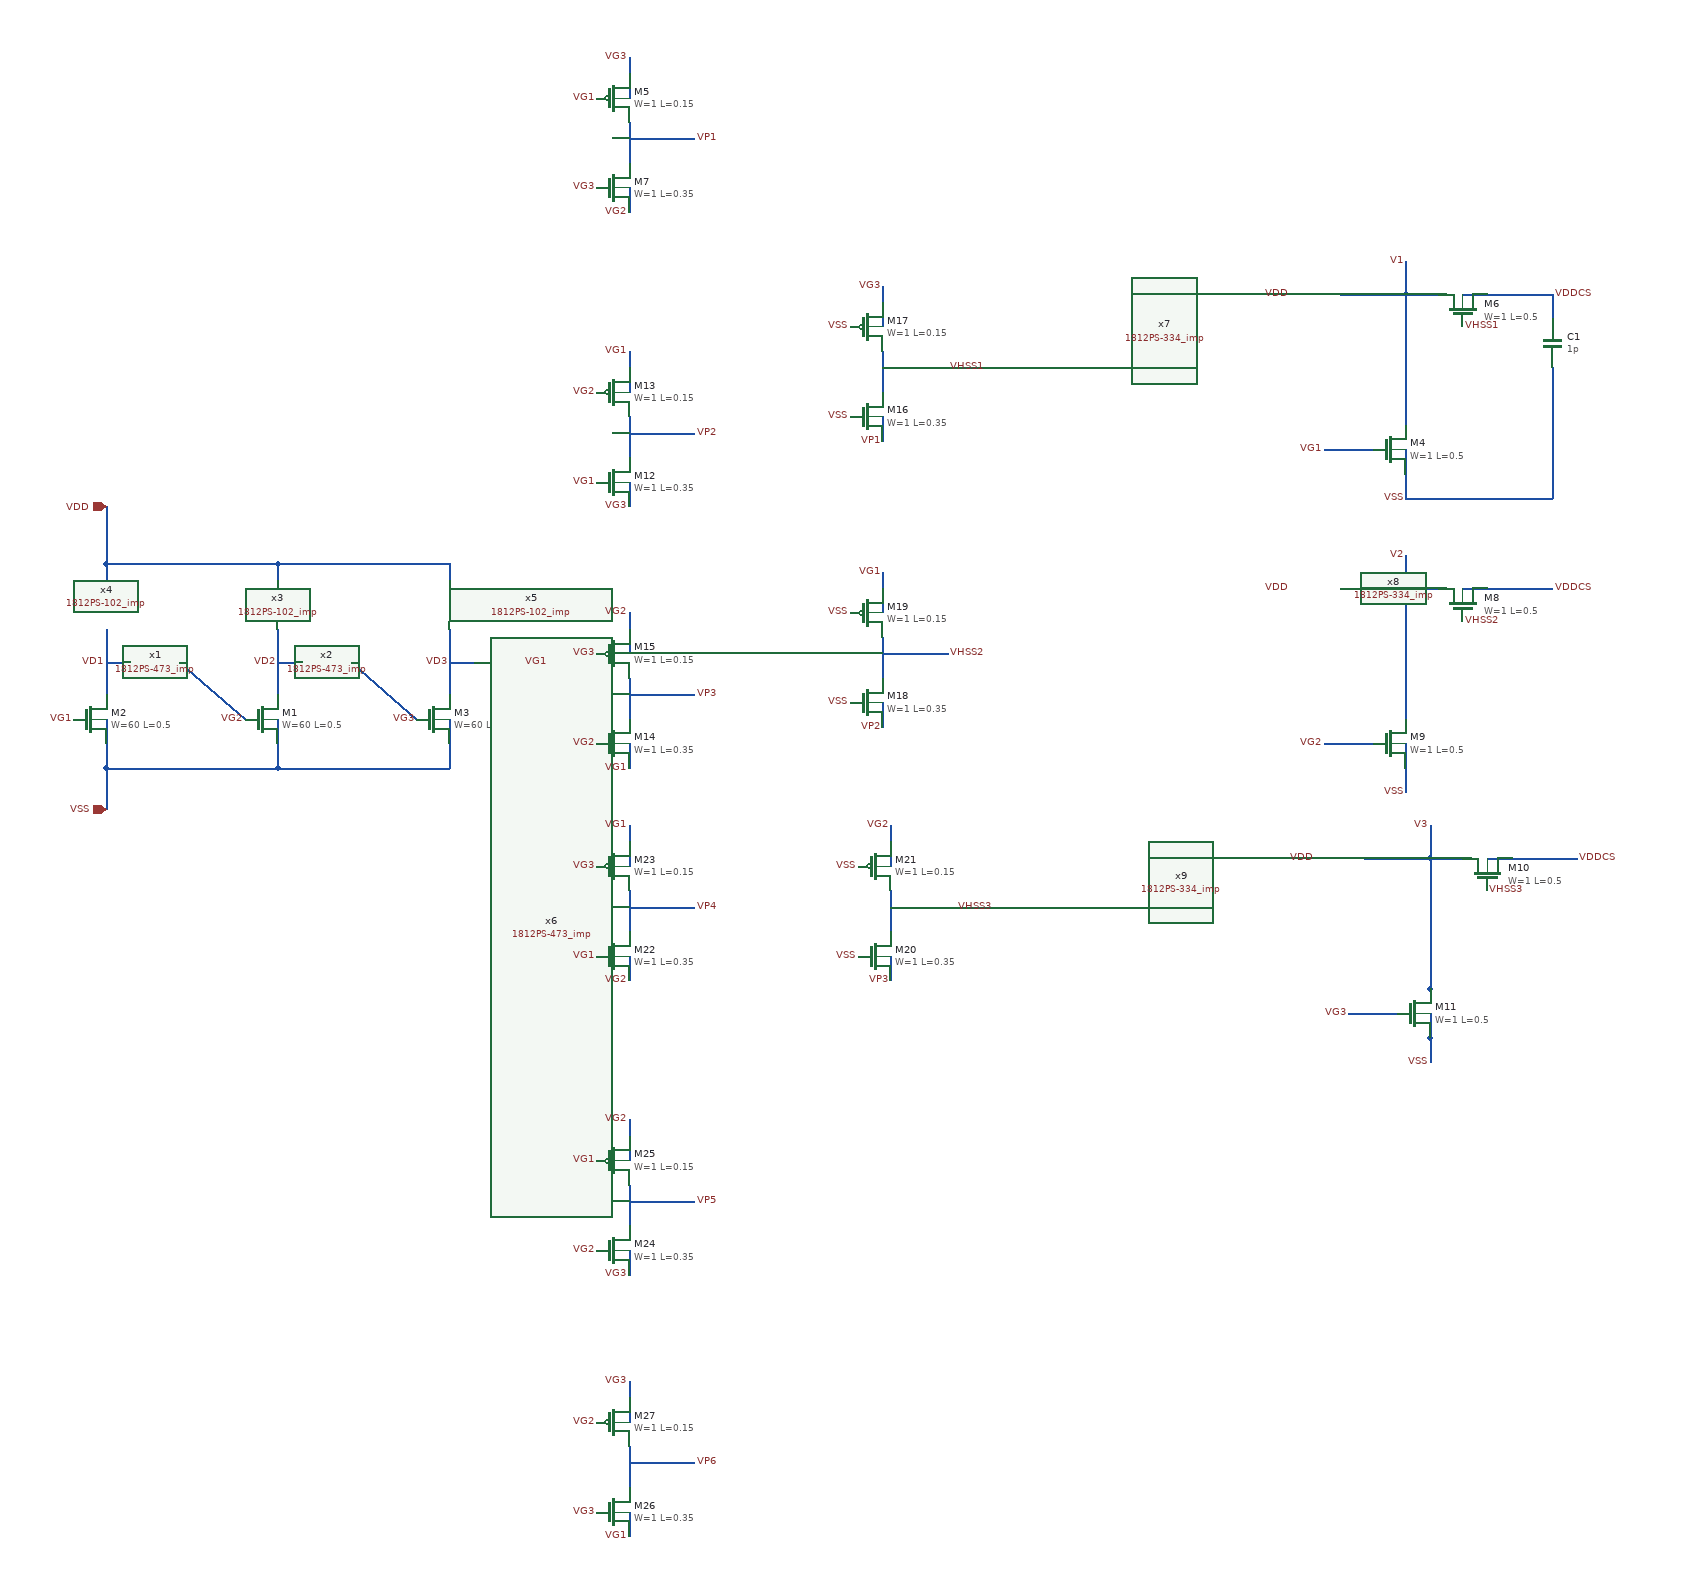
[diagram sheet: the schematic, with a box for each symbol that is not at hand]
v {xschem version=3.4.8RC file_version=1.2}
G {}
K {}
V {}
S {}
E {}
N -140 -190 -140 -170 {lab=VDD}
N -140 -190 70 -190 {lab=VDD}
N 70 -190 70 -170 {lab=VDD}
N 70 -110 70 -30 {lab=VD2}
N 70 -70 70 -30 {lab=VD2}
N -140 -110 -140 -70 {lab=VD1}
N -140 -110 -140 -30 {lab=VD1}
N -140 30 -140 60 {lab=VSS}
N -140 60 70 60 {lab=VSS}
N 70 30 70 60 {lab=VSS}
N -140 -70 -110 -70 {lab=VD1}
N -50 -70 30 0 {lab=VG2}
N -140 0 -140 30 {lab=VSS}
N 70 0 70 30 {lab=VSS}
N -140 -260 -140 -190 {lab=VDD}
N -140 60 -140 110 {lab=VSS}
N 70 -70 100 -70 {lab=VD2}
N 280 -190 280 -170 {lab=VDD}
N 280 -110 280 -30 {lab=VD3}
N 280 -70 280 -30 {lab=VD3}
N 280 30 280 60 {lab=VSS}
N 160 -70 240 0 {lab=VG3}
N 280 0 280 30 {lab=VSS}
N 280 -70 310 -70 {lab=VD3}
N 70 -190 280 -190 {lab=VDD}
N 70 60 280 60 {lab=VSS}
N 1450 -300 1450 -270 {lab=VSS}
N 1350 -330 1410 -330 {lab=VG1}
N 1370 -520 1450 -520 {lab=V1}
N 1450 -520 1450 -360 {lab=V1}
N 1450 -520 1500 -520 {lab=V1}
N 1450 -560 1450 -520 {lab=V1}
N 1530 -520 1560 -520 {lab=VDDCS}
N 1560 -520 1630 -520 {lab=VDDCS}
N 1630 -520 1630 -490 {lab=VDDCS}
N 1630 -430 1630 -270 {lab=VSS}
N 1450 -270 1630 -270 {lab=VSS}
N 500 -650 500 -620 {lab=VG2}
N 500 -730 500 -680 {lab=VP1}
N 500 -790 500 -760 {lab=VG3}
N 500 -810 500 -790 {lab=VG3}
N 500 -710 580 -710 {lab=VP1}
N 1450 60 1450 90 {lab=VSS}
N 1350 30 1410 30 {lab=VG2}
N 1370 -160 1450 -160 {lab=V2}
N 1450 -160 1450 0 {lab=V2}
N 1450 -160 1500 -160 {lab=V2}
N 1450 -200 1450 -160 {lab=V2}
N 1530 -160 1560 -160 {lab=VDDCS}
N 1560 -160 1630 -160 {lab=VDDCS}
N 1480 390 1480 420 {lab=VSS}
N 1380 360 1440 360 {lab=VG3}
N 1400 170 1480 170 {lab=V3}
N 1480 170 1480 330 {lab=V3}
N 1480 170 1530 170 {lab=V3}
N 1480 130 1480 170 {lab=V3}
N 1560 170 1590 170 {lab=VDDCS}
N 1590 170 1660 170 {lab=VDDCS}
N 500 -290 500 -260 {lab=VG3}
N 500 -370 500 -320 {lab=VP2}
N 500 -430 500 -400 {lab=VG1}
N 500 -450 500 -430 {lab=VG1}
N 500 -350 580 -350 {lab=VP2}
N 500 30 500 60 {lab=VG1}
N 500 -50 500 0 {lab=VP3}
N 500 -110 500 -80 {lab=VG2}
N 500 -130 500 -110 {lab=VG2}
N 500 -30 580 -30 {lab=VP3}
N 1450 -330 1450 -300 {lab=VSS}
N 1450 -160 1450 0 {lab=V2}
N 1450 30 1450 60 {lab=VSS}
N 1480 390 1480 420 {lab=VSS}
N 1480 170 1480 330 {lab=V3}
N 1480 170 1480 330 {lab=V3}
N 1480 360 1480 390 {lab=VSS}
N 810 -370 810 -340 {lab=VP1}
N 810 -450 810 -400 {lab=VHSS1}
N 810 -510 810 -480 {lab=VG3}
N 810 -530 810 -510 {lab=VG3}
N 810 -430 890 -430 {lab=VHSS1}
N 810 -20 810 10 {lab=VP2}
N 810 -100 810 -50 {lab=VHSS2}
N 810 -160 810 -130 {lab=VG1}
N 810 -180 810 -160 {lab=VG1}
N 810 -80 890 -80 {lab=VHSS2}
N 820 290 820 320 {lab=VP3}
N 820 210 820 260 {lab=VHSS3}
N 820 150 820 180 {lab=VG2}
N 820 130 820 150 {lab=VG2}
N 820 230 900 230 {lab=VHSS3}
N 1520 -160 1530 -160 {lab=VDDCS}
N 1550 170 1560 170 {lab=VDDCS}
N 1520 -520 1530 -520 {lab=VDDCS}
N 500 290 500 320 {lab=VG2}
N 500 210 500 260 {lab=VP4}
N 500 150 500 180 {lab=VG1}
N 500 130 500 150 {lab=VG1}
N 500 230 580 230 {lab=VP4}
N 500 650 500 680 {lab=VG3}
N 500 570 500 620 {lab=VP5}
N 500 510 500 540 {lab=VG2}
N 500 490 500 510 {lab=VG2}
N 500 590 580 590 {lab=VP5}
N 500 970 500 1000 {lab=VG1}
N 500 890 500 940 {lab=VP6}
N 500 830 500 860 {lab=#net1}
N 500 810 500 830 {lab=#net1}
N 500 910 580 910 {lab=VP6}
C {devices/ipin.sym} -140 110 0 0 {name=p1 lab=VSS
}
C {devices/ipin.sym} -140 -260 0 0 {name=p2 lab=VDD}
C {devices/lab_pin.sym} 30 0 0 0 {name=p5 sig_type=std_logic lab=VG2}
C {devices/lab_pin.sym} -180 0 0 0 {name=p6 sig_type=std_logic lab=VG1}
C {LELO_SVOD_SKY130A/1812PS-102_imp.sym} 70 -140 0 0 {name=x3}
C {LELO_SVOD_SKY130A/1812PS-102_imp.sym} -140 -140 0 0 {name=x4}
C {sky130_fd_pr/nfet_20v0_zvt.sym} 50 0 0 0 {name=M1
W=60
L=0.5
mult=400
model=nfet_20v0_zvt
spiceprefix=X
}
C {sky130_fd_pr/nfet_20v0_zvt.sym} -160 0 0 0 {name=M2
W=60
L=0.5
mult=400
model=nfet_20v0_zvt
spiceprefix=X
}
C {devices/lab_pin.sym} 240 0 0 0 {name=p3 sig_type=std_logic lab=VG3}
C {LELO_SVOD_SKY130A/1812PS-102_imp.sym} 280 -140 0 0 {name=x5}
C {sky130_fd_pr/nfet_20v0_zvt.sym} 260 0 0 0 {name=M3
W=60
L=0.5
mult=400
model=nfet_20v0_zvt
spiceprefix=X
}
C {LELO_SVOD_SKY130A/1812PS-473_imp.sym} -80 -70 3 0 {name=x1}
C {LELO_SVOD_SKY130A/1812PS-473_imp.sym} 130 -70 3 0 {name=x2}
C {LELO_SVOD_SKY130A/1812PS-473_imp.sym} 340 -70 3 0 {name=x6}
C {devices/lab_pin.sym} -140 -70 0 0 {name=p7 sig_type=std_logic lab=VD1}
C {devices/lab_pin.sym} 70 -70 0 0 {name=p8 sig_type=std_logic lab=VD2}
C {devices/lab_pin.sym} 280 -70 0 0 {name=p9 sig_type=std_logic lab=VD3}
C {devices/lab_pin.sym} 1450 -560 3 1 {name=p31 sig_type=std_logic lab=V1}
C {devices/lab_pin.sym} 1350 -330 0 0 {name=p32 sig_type=std_logic lab=VG1}
C {devices/capa.sym} 1630 -460 0 0 {name=C1
m=1
value=1p
footprint=1206
device="ceramic capacitor"}
C {devices/lab_pin.sym} 1630 -520 0 1 {name=p38 sig_type=std_logic lab=VDDCS}
C {LELO_SVOD_SKY130A/1812PS-334_imp.sym} 1340 -520 3 0 {name=x7}
C {devices/lab_pin.sym} 1550 210 0 1 {name=p39 sig_type=std_logic lab=VHSS3}
C {devices/lab_pin.sym} 500 -620 0 0 {name=p11 sig_type=std_logic lab=VG2}
C {devices/lab_pin.sym} 460 -650 0 0 {name=p12 sig_type=std_logic lab=VG3}
C {devices/lab_pin.sym} 460 -760 0 0 {name=p13 sig_type=std_logic lab=VG1}
C {devices/lab_pin.sym} 500 -810 0 0 {name=p14 sig_type=std_logic lab=VG3}
C {sky130_fd_pr/nfet_01v8.sym} 480 -650 0 0 {name=M7
W=1
L=0.35
nf=1 
mult=1
ad="expr('int((@nf + 1)/2) * @W / @nf * 0.29')"
pd="expr('2*int((@nf + 1)/2) * (@W / @nf + 0.29)')"
as="expr('int((@nf + 2)/2) * @W / @nf * 0.29')"
ps="expr('2*int((@nf + 2)/2) * (@W / @nf + 0.29)')"
nrd="expr('0.29 / @W ')" nrs="expr('0.29 / @W ')"
sa=0 sb=0 sd=0
model=nfet_01v8
spiceprefix=X
}
C {devices/lab_pin.sym} 580 -710 0 1 {name=p10 sig_type=std_logic lab=VP1}
C {devices/lab_pin.sym} 1310 -520 2 1 {name=p15 sig_type=std_logic lab=VDD}
C {devices/lab_pin.sym} 1450 -270 2 1 {name=p16 sig_type=std_logic lab=VSS}
C {sky130_fd_pr/pfet_01v8.sym} 480 -760 0 0 {name=M5
W=1
L=0.15
nf=1
mult=1
ad="expr('int((@nf + 1)/2) * @W / @nf * 0.29')"
pd="expr('2*int((@nf + 1)/2) * (@W / @nf + 0.29)')"
as="expr('int((@nf + 2)/2) * @W / @nf * 0.29')"
ps="expr('2*int((@nf + 2)/2) * (@W / @nf + 0.29)')"
nrd="expr('0.29 / @W ')" nrs="expr('0.29 / @W ')"
sa=0 sb=0 sd=0
model=pfet_01v8
spiceprefix=X
}
C {devices/lab_pin.sym} 1450 -200 3 1 {name=p17 sig_type=std_logic lab=V2}
C {devices/lab_pin.sym} 1630 -160 0 1 {name=p19 sig_type=std_logic lab=VDDCS}
C {LELO_SVOD_SKY130A/1812PS-334_imp.sym} 1340 -160 3 0 {name=x8}
C {devices/lab_pin.sym} 1310 -160 2 1 {name=p21 sig_type=std_logic lab=VDD}
C {devices/lab_pin.sym} 1450 90 2 1 {name=p22 sig_type=std_logic lab=VSS}
C {devices/lab_pin.sym} 1480 130 3 1 {name=p23 sig_type=std_logic lab=V3}
C {devices/lab_pin.sym} 1380 360 0 0 {name=p24 sig_type=std_logic lab=VG3}
C {devices/lab_pin.sym} 1660 170 0 1 {name=p25 sig_type=std_logic lab=VDDCS}
C {LELO_SVOD_SKY130A/1812PS-334_imp.sym} 1370 170 3 0 {name=x9}
C {devices/lab_pin.sym} 1520 -120 0 1 {name=p26 sig_type=std_logic lab=VHSS2}
C {devices/lab_pin.sym} 1340 170 2 1 {name=p27 sig_type=std_logic lab=VDD}
C {devices/lab_pin.sym} 1480 420 2 1 {name=p28 sig_type=std_logic lab=VSS}
C {devices/lab_pin.sym} 500 -450 0 0 {name=p33 sig_type=std_logic lab=VG1}
C {sky130_fd_pr/nfet_01v8.sym} 480 -290 0 0 {name=M12
W=1
L=0.35
nf=1 
mult=1
ad="expr('int((@nf + 1)/2) * @W / @nf * 0.29')"
pd="expr('2*int((@nf + 1)/2) * (@W / @nf + 0.29)')"
as="expr('int((@nf + 2)/2) * @W / @nf * 0.29')"
ps="expr('2*int((@nf + 2)/2) * (@W / @nf + 0.29)')"
nrd="expr('0.29 / @W ')" nrs="expr('0.29 / @W ')"
sa=0 sb=0 sd=0
model=nfet_01v8
spiceprefix=X
}
C {devices/lab_pin.sym} 580 -350 0 1 {name=p35 sig_type=std_logic lab=VP2}
C {sky130_fd_pr/pfet_01v8.sym} 480 -400 0 0 {name=M13
W=1
L=0.15
nf=1
mult=1
ad="expr('int((@nf + 1)/2) * @W / @nf * 0.29')"
pd="expr('2*int((@nf + 1)/2) * (@W / @nf + 0.29)')"
as="expr('int((@nf + 2)/2) * @W / @nf * 0.29')"
ps="expr('2*int((@nf + 2)/2) * (@W / @nf + 0.29)')"
nrd="expr('0.29 / @W ')" nrs="expr('0.29 / @W ')"
sa=0 sb=0 sd=0
model=pfet_01v8
spiceprefix=X
}
C {sky130_fd_pr/nfet_01v8.sym} 480 30 0 0 {name=M14
W=1
L=0.35
nf=1 
mult=1
ad="expr('int((@nf + 1)/2) * @W / @nf * 0.29')"
pd="expr('2*int((@nf + 1)/2) * (@W / @nf + 0.29)')"
as="expr('int((@nf + 2)/2) * @W / @nf * 0.29')"
ps="expr('2*int((@nf + 2)/2) * (@W / @nf + 0.29)')"
nrd="expr('0.29 / @W ')" nrs="expr('0.29 / @W ')"
sa=0 sb=0 sd=0
model=nfet_01v8
spiceprefix=X
}
C {devices/lab_pin.sym} 580 -30 0 1 {name=p42 sig_type=std_logic lab=VP3}
C {sky130_fd_pr/pfet_01v8.sym} 480 -80 0 0 {name=M15
W=1
L=0.15
nf=1
mult=1
ad="expr('int((@nf + 1)/2) * @W / @nf * 0.29')"
pd="expr('2*int((@nf + 1)/2) * (@W / @nf + 0.29)')"
as="expr('int((@nf + 2)/2) * @W / @nf * 0.29')"
ps="expr('2*int((@nf + 2)/2) * (@W / @nf + 0.29)')"
nrd="expr('0.29 / @W ')" nrs="expr('0.29 / @W ')"
sa=0 sb=0 sd=0
model=pfet_01v8
spiceprefix=X
}
C {devices/lab_pin.sym} 1350 30 0 0 {name=p18 sig_type=std_logic lab=VG2}
C {devices/lab_pin.sym} 460 -400 0 0 {name=p30 sig_type=std_logic lab=VG2}
C {devices/lab_pin.sym} 500 -260 0 0 {name=p36 sig_type=std_logic lab=VG3}
C {devices/lab_pin.sym} 460 -290 0 0 {name=p37 sig_type=std_logic lab=VG1}
C {devices/lab_pin.sym} 460 30 0 0 {name=p29 sig_type=std_logic lab=VG2}
C {devices/lab_pin.sym} 500 -130 0 0 {name=p34 sig_type=std_logic lab=VG2}
C {devices/lab_pin.sym} 460 -80 0 0 {name=p40 sig_type=std_logic lab=VG3}
C {devices/lab_pin.sym} 500 60 0 0 {name=p43 sig_type=std_logic lab=VG1}
C {sky130_fd_pr/nfet_03v3_nvt.sym} 1430 -330 0 0 {name=M4
W=1
L=0.5
nf=1
mult=1000
ad="expr('int((@nf + 1)/2) * @W / @nf * 0.29')"
pd="expr('2*int((@nf + 1)/2) * (@W / @nf + 0.29)')"
as="expr('int((@nf + 2)/2) * @W / @nf * 0.29')"
ps="expr('2*int((@nf + 2)/2) * (@W / @nf + 0.29)')"
nrd="expr('0.29 / @W ')" nrs="expr('0.29 / @W ')"
sa=0 sb=0 sd=0
model=nfet_03v3_nvt
spiceprefix=X
}
C {sky130_fd_pr/nfet_03v3_nvt.sym} 1430 30 0 0 {name=M9
W=1
L=0.5
nf=1
mult=1000
ad="expr('int((@nf + 1)/2) * @W / @nf * 0.29')"
pd="expr('2*int((@nf + 1)/2) * (@W / @nf + 0.29)')"
as="expr('int((@nf + 2)/2) * @W / @nf * 0.29')"
ps="expr('2*int((@nf + 2)/2) * (@W / @nf + 0.29)')"
nrd="expr('0.29 / @W ')" nrs="expr('0.29 / @W ')"
sa=0 sb=0 sd=0
model=nfet_03v3_nvt
spiceprefix=X
}
C {sky130_fd_pr/nfet_03v3_nvt.sym} 1460 360 0 0 {name=M11
W=1
L=0.5
nf=1
mult=1000
ad="expr('int((@nf + 1)/2) * @W / @nf * 0.29')"
pd="expr('2*int((@nf + 1)/2) * (@W / @nf + 0.29)')"
as="expr('int((@nf + 2)/2) * @W / @nf * 0.29')"
ps="expr('2*int((@nf + 2)/2) * (@W / @nf + 0.29)')"
nrd="expr('0.29 / @W ')" nrs="expr('0.29 / @W ')"
sa=0 sb=0 sd=0
model=nfet_03v3_nvt
spiceprefix=X
}
C {devices/lab_pin.sym} 810 -340 0 0 {name=p41 sig_type=std_logic lab=VP1}
C {devices/lab_pin.sym} 770 -370 0 0 {name=p44 sig_type=std_logic lab=VSS}
C {devices/lab_pin.sym} 770 -480 0 0 {name=p45 sig_type=std_logic lab=VSS}
C {devices/lab_pin.sym} 810 -530 0 0 {name=p46 sig_type=std_logic lab=VG3}
C {sky130_fd_pr/nfet_01v8.sym} 790 -370 0 0 {name=M16
W=1
L=0.35
nf=1 
mult=1
ad="expr('int((@nf + 1)/2) * @W / @nf * 0.29')"
pd="expr('2*int((@nf + 1)/2) * (@W / @nf + 0.29)')"
as="expr('int((@nf + 2)/2) * @W / @nf * 0.29')"
ps="expr('2*int((@nf + 2)/2) * (@W / @nf + 0.29)')"
nrd="expr('0.29 / @W ')" nrs="expr('0.29 / @W ')"
sa=0 sb=0 sd=0
model=nfet_01v8
spiceprefix=X
lab=VHSS1}
C {devices/lab_pin.sym} 890 -430 0 1 {name=p47 sig_type=std_logic lab=VHSS1}
C {sky130_fd_pr/pfet_01v8.sym} 790 -480 0 0 {name=M17
W=1
L=0.15
nf=1
mult=1
ad="expr('int((@nf + 1)/2) * @W / @nf * 0.29')"
pd="expr('2*int((@nf + 1)/2) * (@W / @nf + 0.29)')"
as="expr('int((@nf + 2)/2) * @W / @nf * 0.29')"
ps="expr('2*int((@nf + 2)/2) * (@W / @nf + 0.29)')"
nrd="expr('0.29 / @W ')" nrs="expr('0.29 / @W ')"
sa=0 sb=0 sd=0
model=pfet_01v8
spiceprefix=X
lab=VHSS1}
C {devices/lab_pin.sym} 1520 -480 0 1 {name=p20 sig_type=std_logic lab=VHSS1}
C {devices/lab_pin.sym} 810 10 0 0 {name=p48 sig_type=std_logic lab=VP2}
C {devices/lab_pin.sym} 770 -20 0 0 {name=p49 sig_type=std_logic lab=VSS}
C {devices/lab_pin.sym} 770 -130 0 0 {name=p50 sig_type=std_logic lab=VSS}
C {devices/lab_pin.sym} 810 -180 0 0 {name=p51 sig_type=std_logic lab=VG1}
C {sky130_fd_pr/nfet_01v8.sym} 790 -20 0 0 {name=M18
W=1
L=0.35
nf=1 
mult=1
ad="expr('int((@nf + 1)/2) * @W / @nf * 0.29')"
pd="expr('2*int((@nf + 1)/2) * (@W / @nf + 0.29)')"
as="expr('int((@nf + 2)/2) * @W / @nf * 0.29')"
ps="expr('2*int((@nf + 2)/2) * (@W / @nf + 0.29)')"
nrd="expr('0.29 / @W ')" nrs="expr('0.29 / @W ')"
sa=0 sb=0 sd=0
model=nfet_01v8
spiceprefix=X
lab=VHSS1}
C {devices/lab_pin.sym} 890 -80 0 1 {name=p52 sig_type=std_logic lab=VHSS2}
C {sky130_fd_pr/pfet_01v8.sym} 790 -130 0 0 {name=M19
W=1
L=0.15
nf=1
mult=1
ad="expr('int((@nf + 1)/2) * @W / @nf * 0.29')"
pd="expr('2*int((@nf + 1)/2) * (@W / @nf + 0.29)')"
as="expr('int((@nf + 2)/2) * @W / @nf * 0.29')"
ps="expr('2*int((@nf + 2)/2) * (@W / @nf + 0.29)')"
nrd="expr('0.29 / @W ')" nrs="expr('0.29 / @W ')"
sa=0 sb=0 sd=0
model=pfet_01v8
spiceprefix=X
lab=VHSS1}
C {devices/lab_pin.sym} 820 320 0 0 {name=p53 sig_type=std_logic lab=VP3}
C {devices/lab_pin.sym} 780 290 0 0 {name=p54 sig_type=std_logic lab=VSS}
C {devices/lab_pin.sym} 780 180 0 0 {name=p55 sig_type=std_logic lab=VSS}
C {devices/lab_pin.sym} 820 130 0 0 {name=p56 sig_type=std_logic lab=VG2}
C {sky130_fd_pr/nfet_01v8.sym} 800 290 0 0 {name=M20
W=1
L=0.35
nf=1 
mult=1
ad="expr('int((@nf + 1)/2) * @W / @nf * 0.29')"
pd="expr('2*int((@nf + 1)/2) * (@W / @nf + 0.29)')"
as="expr('int((@nf + 2)/2) * @W / @nf * 0.29')"
ps="expr('2*int((@nf + 2)/2) * (@W / @nf + 0.29)')"
nrd="expr('0.29 / @W ')" nrs="expr('0.29 / @W ')"
sa=0 sb=0 sd=0
model=nfet_01v8
spiceprefix=X
lab=VHSS1}
C {devices/lab_pin.sym} 900 230 0 1 {name=p57 sig_type=std_logic lab=VHSS3}
C {sky130_fd_pr/pfet_01v8.sym} 800 180 0 0 {name=M21
W=1
L=0.15
nf=1
mult=1
ad="expr('int((@nf + 1)/2) * @W / @nf * 0.29')"
pd="expr('2*int((@nf + 1)/2) * (@W / @nf + 0.29)')"
as="expr('int((@nf + 2)/2) * @W / @nf * 0.29')"
ps="expr('2*int((@nf + 2)/2) * (@W / @nf + 0.29)')"
nrd="expr('0.29 / @W ')" nrs="expr('0.29 / @W ')"
sa=0 sb=0 sd=0
model=pfet_01v8
spiceprefix=X
lab=VHSS1}
C {sky130_fd_pr/nfet_03v3_nvt.sym} 1520 -140 3 0 {name=M8
W=1
L=0.5
nf=1
mult=1
ad="expr('int((@nf + 1)/2) * @W / @nf * 0.29')"
pd="expr('2*int((@nf + 1)/2) * (@W / @nf + 0.29)')"
as="expr('int((@nf + 2)/2) * @W / @nf * 0.29')"
ps="expr('2*int((@nf + 2)/2) * (@W / @nf + 0.29)')"
nrd="expr('0.29 / @W ')" nrs="expr('0.29 / @W ')"
sa=0 sb=0 sd=0
model=nfet_03v3_nvt
spiceprefix=X
}
C {sky130_fd_pr/nfet_03v3_nvt.sym} 1520 -500 3 0 {name=M6
W=1
L=0.5
nf=1
mult=1
ad="expr('int((@nf + 1)/2) * @W / @nf * 0.29')"
pd="expr('2*int((@nf + 1)/2) * (@W / @nf + 0.29)')"
as="expr('int((@nf + 2)/2) * @W / @nf * 0.29')"
ps="expr('2*int((@nf + 2)/2) * (@W / @nf + 0.29)')"
nrd="expr('0.29 / @W ')" nrs="expr('0.29 / @W ')"
sa=0 sb=0 sd=0
model=nfet_03v3_nvt
spiceprefix=X
}
C {sky130_fd_pr/nfet_03v3_nvt.sym} 1550 190 3 0 {name=M10
W=1
L=0.5
nf=1
mult=1
ad="expr('int((@nf + 1)/2) * @W / @nf * 0.29')"
pd="expr('2*int((@nf + 1)/2) * (@W / @nf + 0.29)')"
as="expr('int((@nf + 2)/2) * @W / @nf * 0.29')"
ps="expr('2*int((@nf + 2)/2) * (@W / @nf + 0.29)')"
nrd="expr('0.29 / @W ')" nrs="expr('0.29 / @W ')"
sa=0 sb=0 sd=0
model=nfet_03v3_nvt
spiceprefix=X
}
C {devices/lab_pin.sym} 370 -70 0 1 {name=p4 sig_type=std_logic lab=VG1}
C {devices/lab_pin.sym} 500 320 0 0 {name=p58 sig_type=std_logic lab=VG2}
C {devices/lab_pin.sym} 460 180 0 0 {name=p59 sig_type=std_logic lab=VG3}
C {devices/lab_pin.sym} 460 290 0 0 {name=p60 sig_type=std_logic lab=VG1}
C {sky130_fd_pr/nfet_01v8.sym} 480 290 0 0 {name=M22
W=1
L=0.35
nf=1 
mult=1
ad="expr('int((@nf + 1)/2) * @W / @nf * 0.29')"
pd="expr('2*int((@nf + 1)/2) * (@W / @nf + 0.29)')"
as="expr('int((@nf + 2)/2) * @W / @nf * 0.29')"
ps="expr('2*int((@nf + 2)/2) * (@W / @nf + 0.29)')"
nrd="expr('0.29 / @W ')" nrs="expr('0.29 / @W ')"
sa=0 sb=0 sd=0
model=nfet_01v8
spiceprefix=X
}
C {devices/lab_pin.sym} 580 230 0 1 {name=p62 sig_type=std_logic lab=VP4}
C {sky130_fd_pr/pfet_01v8.sym} 480 180 0 0 {name=M23
W=1
L=0.15
nf=1
mult=1
ad="expr('int((@nf + 1)/2) * @W / @nf * 0.29')"
pd="expr('2*int((@nf + 1)/2) * (@W / @nf + 0.29)')"
as="expr('int((@nf + 2)/2) * @W / @nf * 0.29')"
ps="expr('2*int((@nf + 2)/2) * (@W / @nf + 0.29)')"
nrd="expr('0.29 / @W ')" nrs="expr('0.29 / @W ')"
sa=0 sb=0 sd=0
model=pfet_01v8
spiceprefix=X
}
C {sky130_fd_pr/nfet_01v8.sym} 480 650 0 0 {name=M24
W=1
L=0.35
nf=1 
mult=1
ad="expr('int((@nf + 1)/2) * @W / @nf * 0.29')"
pd="expr('2*int((@nf + 1)/2) * (@W / @nf + 0.29)')"
as="expr('int((@nf + 2)/2) * @W / @nf * 0.29')"
ps="expr('2*int((@nf + 2)/2) * (@W / @nf + 0.29)')"
nrd="expr('0.29 / @W ')" nrs="expr('0.29 / @W ')"
sa=0 sb=0 sd=0
model=nfet_01v8
spiceprefix=X
}
C {devices/lab_pin.sym} 580 590 0 1 {name=p64 sig_type=std_logic lab=VP5}
C {sky130_fd_pr/pfet_01v8.sym} 480 540 0 0 {name=M25
W=1
L=0.15
nf=1
mult=1
ad="expr('int((@nf + 1)/2) * @W / @nf * 0.29')"
pd="expr('2*int((@nf + 1)/2) * (@W / @nf + 0.29)')"
as="expr('int((@nf + 2)/2) * @W / @nf * 0.29')"
ps="expr('2*int((@nf + 2)/2) * (@W / @nf + 0.29)')"
nrd="expr('0.29 / @W ')" nrs="expr('0.29 / @W ')"
sa=0 sb=0 sd=0
model=pfet_01v8
spiceprefix=X
}
C {sky130_fd_pr/nfet_01v8.sym} 480 970 0 0 {name=M26
W=1
L=0.35
nf=1 
mult=1
ad="expr('int((@nf + 1)/2) * @W / @nf * 0.29')"
pd="expr('2*int((@nf + 1)/2) * (@W / @nf + 0.29)')"
as="expr('int((@nf + 2)/2) * @W / @nf * 0.29')"
ps="expr('2*int((@nf + 2)/2) * (@W / @nf + 0.29)')"
nrd="expr('0.29 / @W ')" nrs="expr('0.29 / @W ')"
sa=0 sb=0 sd=0
model=nfet_01v8
spiceprefix=X
}
C {devices/lab_pin.sym} 580 910 0 1 {name=p65 sig_type=std_logic lab=VP6}
C {sky130_fd_pr/pfet_01v8.sym} 480 860 0 0 {name=M27
W=1
L=0.15
nf=1
mult=1
ad="expr('int((@nf + 1)/2) * @W / @nf * 0.29')"
pd="expr('2*int((@nf + 1)/2) * (@W / @nf + 0.29)')"
as="expr('int((@nf + 2)/2) * @W / @nf * 0.29')"
ps="expr('2*int((@nf + 2)/2) * (@W / @nf + 0.29)')"
nrd="expr('0.29 / @W ')" nrs="expr('0.29 / @W ')"
sa=0 sb=0 sd=0
model=pfet_01v8
spiceprefix=X
}
C {devices/lab_pin.sym} 460 650 0 0 {name=p66 sig_type=std_logic lab=VG2}
C {devices/lab_pin.sym} 500 680 0 0 {name=p67 sig_type=std_logic lab=VG3}
C {devices/lab_pin.sym} 460 540 0 0 {name=p68 sig_type=std_logic lab=VG1}
C {devices/lab_pin.sym} 460 860 0 0 {name=p69 sig_type=std_logic lab=VG2}
C {devices/lab_pin.sym} 460 970 0 0 {name=p71 sig_type=std_logic lab=VG3}
C {devices/lab_pin.sym} 500 1000 0 0 {name=p72 sig_type=std_logic lab=VG1}
C {devices/lab_pin.sym} 500 130 0 0 {name=p61 sig_type=std_logic lab=VG1}
C {devices/lab_pin.sym} 500 490 0 0 {name=p63 sig_type=std_logic lab=VG2}
C {devices/lab_pin.sym} 500 810 0 0 {name=p70 sig_type=std_logic lab=VG3}
